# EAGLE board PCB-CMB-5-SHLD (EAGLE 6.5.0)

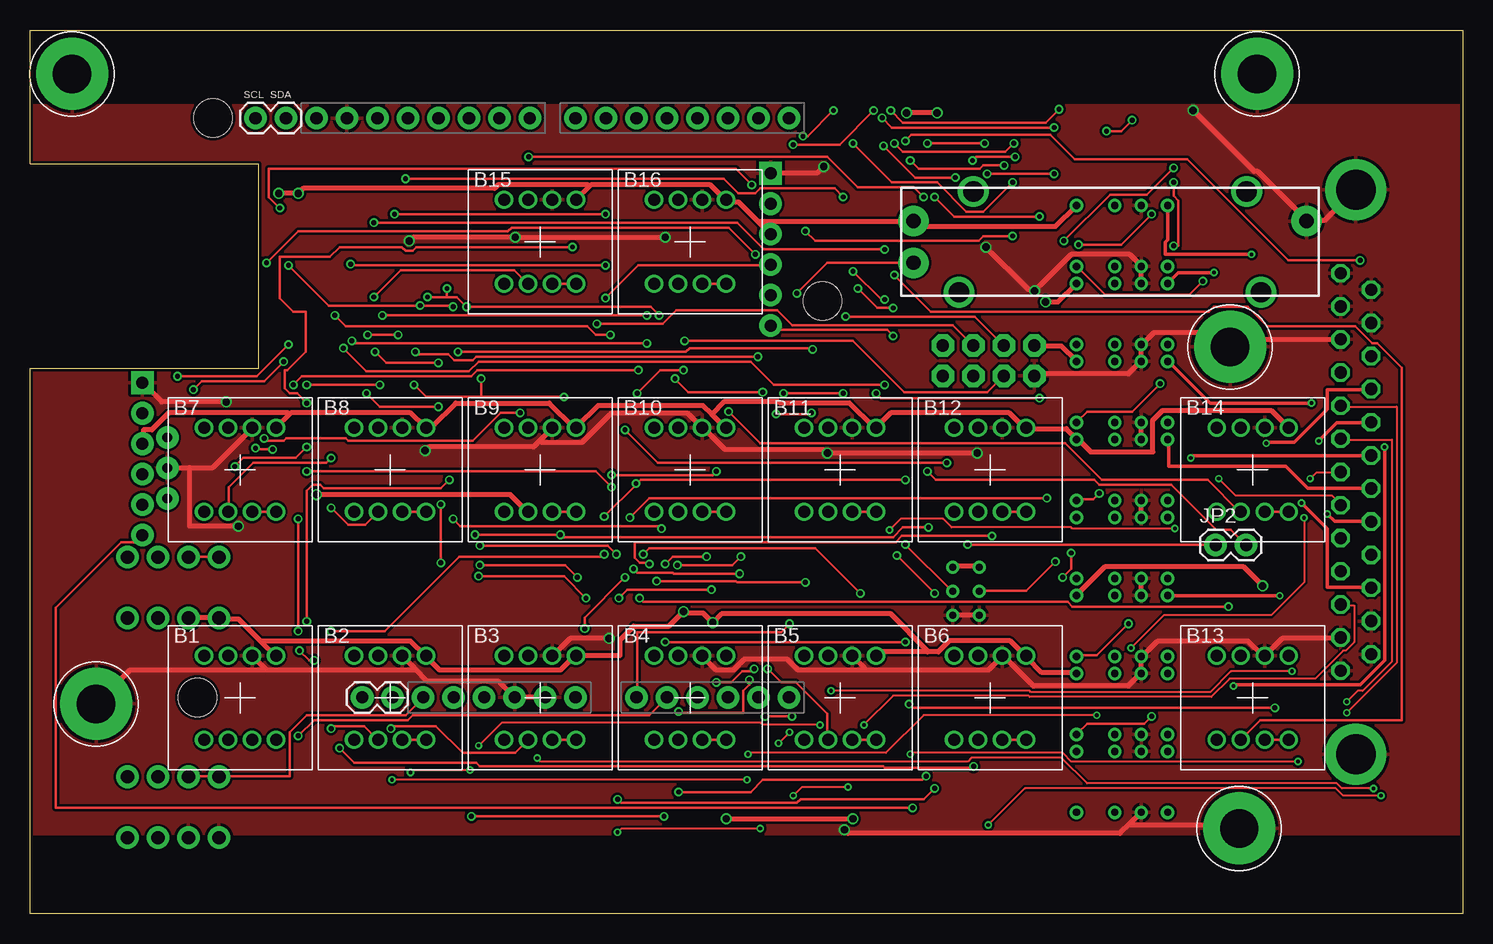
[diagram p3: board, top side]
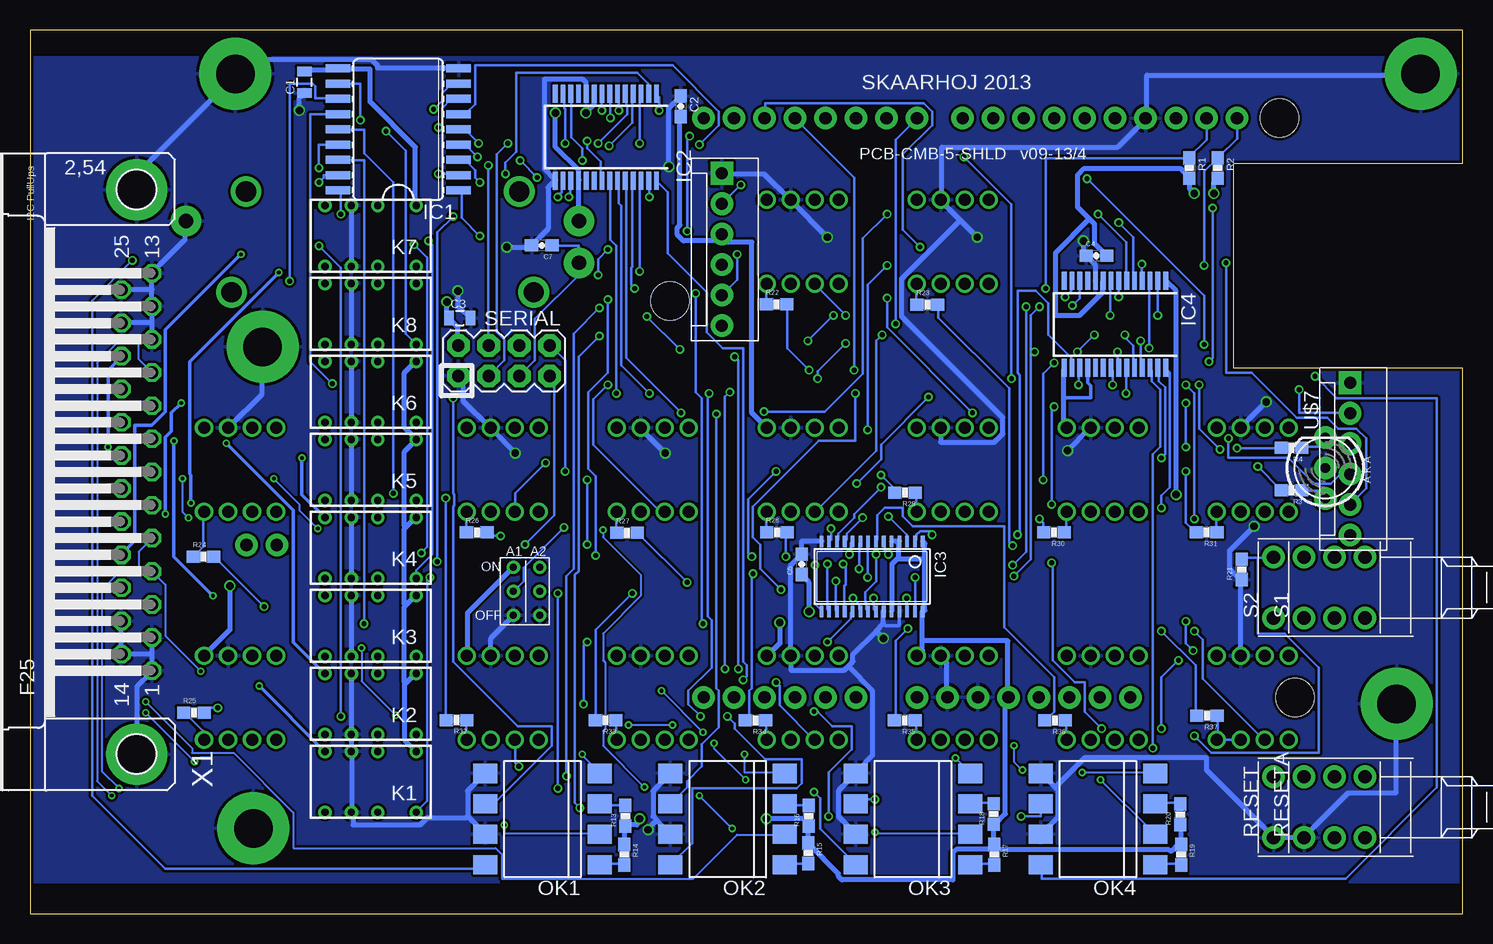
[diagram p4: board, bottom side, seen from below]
Size 119.38 x 73.66 mm. Coordinates in mm from the lower left corner, seen from the top.
Outline: 0,0 0,45.47 19.05,45.47 19.05,62.5 0,62.5 0,73.66 119.38,73.66 119.38,0 0,0
Copper layers (1*16): Top 0.035mm / dielectric 1.5mm / Bottom 0.035mm
Design rules "Fusion_eagle_rule_v1.1": minimum track width 6mil, minimum drill 12mil, track to track 6mil, track to pad 6mil, pad to pad 6mil, via to via 6mil, smd to smd 0mil, copper to edge 10mil, drill to drill 10mil, minimum pad ring 10mil, minimum via ring 6mil, stop-mask expansion 2mil, vias tented up to drill 100mil, thermal gap 10mil
Net classes: 0 default: width 0.203 mm, drill 0.406 mm, clearance 0.203 mm; 1 PWR: width 0.406 mm, drill 0.61 mm, clearance 0.203 mm; 2 RELAY LINES: width 0.305 mm, clearance 0.203 mm; 3 INput lines: clearance 0.203 mm
Holes 3.2 mm at 66.04,51.07 15.24,66.31 13.97,18.05
tRestrict: area 0,0 to 120,6.5; area 0,67.5 to 120,74
bRestrict: area 0,71.5 to 120,74; area 0,0 to 120,2.5

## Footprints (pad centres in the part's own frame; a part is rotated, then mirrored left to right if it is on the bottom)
NKK-NP01 = drill 1: 1 1,3.5; 2 -1,-3.5; L1 3,-3.5; L2 1,-3.5; L3 -1,3.5; L4 -3,3.5; LC1 3,3.5; LC2 -3,-3.5
0805 = smd 0.8 x 1.2: 1 -0.9,0; 2 0.9,0
0603-CAP = smd 1.1 x 1: 1 -0.85,0; 2 0.85,0
DUEMILANOVE_VIAS = drill 1.016 pad 1.88: 3.3V 50.8,13.97; 5V 50.8,16.51; A0 50.8,29.21; A1 50.8,31.75; A2 50.8,34.29; A3 50.8,36.83; A4 50.8,39.37; A5 50.8,41.91; AREF 2.54,2.54; D2 2.54,36.83; D3 2.54,34.29; D4 2.54,31.75; D5 2.54,29.21; D6 2.54,26.67; D7 2.54,24.13; D8 2.54,20.32; D9 2.54,17.78; D10 2.54,15.24; D11 2.54,12.7; D12 2.54,10.16; D13 2.54,7.62; GND@0 50.8,19.05; GND@1 50.8,21.59; GND@2 2.54,5.08; RES 50.8,11.43; RX 2.54,41.91; TX 2.54,39.37; VIN 50.8,24.13
SO18W = smd 0.66 x 2.032: 1 -5.08,-5.029; 2 -3.81,-5.029; 3 -2.54,-5.029; 4 -1.27,-5.029; 5 0,-5.029; 6 1.27,-5.029; 7 2.54,-5.029; 8 3.81,-5.029; 9 5.08,-5.029; 10 5.08,5.029; 11 3.81,5.029; 12 2.54,5.029; 13 1.27,5.029; 14 0,5.029; 15 -1.27,5.029; 16 -2.54,5.029; 17 -3.81,5.029; 18 -5.08,5.029
SSOP28 = smd 0.4 x 1.5: 1 -4.225,-3.625; 2 -3.575,-3.625; 3 -2.925,-3.625; 4 -2.275,-3.625; 5 -1.625,-3.625; 6 -0.975,-3.625; 7 -0.325,-3.625; 8 0.325,-3.625; 9 0.975,-3.625; 10 1.625,-3.625; 11 2.275,-3.625; 12 2.925,-3.625; 13 3.575,-3.625; 14 4.225,-3.625; 15 4.225,3.625; 16 3.575,3.625; 17 2.925,3.625; 18 2.275,3.625; 19 1.625,3.625; 20 0.975,3.625; 21 0.325,3.625; 22 -0.325,3.625; 23 -0.975,3.625; 24 -1.625,3.625; 25 -2.275,3.625; 26 -2.925,3.625; 27 -3.575,3.625; 28 -4.225,3.625
TSSOP28 = smd 0.305 x 0.991: 1 -4.225,-2.918; 2 -3.575,-2.918; 3 -2.925,-2.918; 4 -2.275,-2.918; 5 -1.625,-2.918; 6 -0.975,-2.918; 7 -0.325,-2.918; 8 0.325,-2.918; 9 0.975,-2.918; 10 1.625,-2.918; 11 2.275,-2.918; 12 2.925,-2.918; 13 3.575,-2.918; 14 4.225,-2.918; 15 4.225,2.918; 16 3.575,2.918; 17 2.925,2.918; 18 2.275,2.918; 19 1.625,2.918; 20 0.975,2.918; 21 0.325,2.918; 22 -0.325,2.918; 23 -0.975,2.918; 24 -1.625,2.918; 25 -2.275,2.918; 26 -2.925,2.918; 27 -3.575,2.918; 28 -4.225,2.918
1X02 = drill 1.016 pad 1.88: 1 0,0; 2 2.54,0
MOLEX-1X6 = drill 1.016 pad 1.88 square: 1 0,0 | drill 1.016 pad 1.88: 2 2.54,0; 3 5.08,0; 4 7.62,0; 5 10.16,0; 6 12.7,0
DS2Y = drill 0.6: 1 1.2,0.46; 16 1.2,5.54; O1 4.4,0.46; O2 4.4,5.54; P1 6.6,0.46; P2 6.6,5.54; S1 8.8,0.46; S2 8.8,5.54
DIL8-SMD = smd 1.6 x 2: 1 -3.81,-4.77; 2 -1.27,-4.77; 3 1.27,-4.77; 4 3.81,-4.77; 5 3.81,4.77; 6 1.27,4.77; 7 -1.27,4.77; 8 -3.81,4.77
SLIDER20 = drill 1.194 pad 2.54: 1 -16.383,1.74; 2A -16.383,-1.74; 3 16.383,1.74 | drill 1.702: P$1 -11.392,4.191; P$2 11.392,4.191; P$3 12.598,-4.191; P$4 -12.598,-4.191
0603-RES = smd 1.1 x 1: 1 -0.85,0; 2 0.85,0
PUSHBUTTON = drill 1.1 pad 1.88: 1 2.54,2.54; 2 2.54,-2.54; 3 -2.54,2.54; 4 -2.54,-2.54
2X4 = drill 1.016 pad 1.88 octagon: 1 -3.81,-1.27; 2 -3.81,1.27; 3 -1.27,-1.27; 4 -1.27,1.27; 5 1.27,-1.27; 6 1.27,1.27; 7 3.81,-1.27; 8 3.81,1.27
3.2MMPAD6MM = drill 3.2 pad 6: P$1 0,0
LED5MM-BICOLOR = drill 0.813 pad 1.88: A2 2.54,0; A3 -2.54,0; K1 0,0
2BITADDR = drill 0.6: A1 0,0; A2 2.2,0; H2 0,2; H3 2.2,2; L2 0,-2; L3 2.2,-2
F25HP = drill 1.016 octagon: 1 -16.561,-1.27; 2 -13.792,-1.27; 3 -11.049,-1.27; 4 -8.28,-1.27; 5 -5.512,-1.27; 6 -2.769,-1.27; 7 0,-1.27; 8 2.769,-1.27; 9 5.512,-1.27; 10 8.28,-1.27; 11 11.049,-1.27; 12 13.792,-1.27; 13 16.561,-1.27; 14 -15.189,1.27; 15 -12.421,1.27; 16 -9.652,1.27; 17 -6.909,1.27; 18 -4.14,1.27; 19 -1.372,1.27; 20 1.372,1.27; 21 4.14,1.27; 22 6.909,1.27; 23 9.652,1.27; 24 12.421,1.27; 25 15.189,1.27 | drill 3.302 pad 5.08: G1 -23.52,0; G2 23.52,0

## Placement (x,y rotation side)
B1  NKK-NP01-SINGLECOLOR  [NKK-NP01]  17.5,18 0 top
B2  NKK-NP01-SINGLECOLOR  [NKK-NP01]  30,18 0 top
B3  NKK-NP01-SINGLECOLOR  [NKK-NP01]  42.5,18 0 top
B4  NKK-NP01-SINGLECOLOR  [NKK-NP01]  55,18 0 top
B5  NKK-NP01-SINGLECOLOR  [NKK-NP01]  67.5,18 0 top
B6  NKK-NP01-SINGLECOLOR  [NKK-NP01]  80,18 0 top
B7  NKK-NP01-SINGLECOLOR  [NKK-NP01]  17.5,37 0 top
B8  NKK-NP01-SINGLECOLOR  [NKK-NP01]  30,37 0 top
B9  NKK-NP01-SINGLECOLOR  [NKK-NP01]  42.5,37 0 top
B10  NKK-NP01-SINGLECOLOR  [NKK-NP01]  55,37 0 top
B11  NKK-NP01-SINGLECOLOR  [NKK-NP01]  67.5,37 0 top
B12  NKK-NP01-SINGLECOLOR  [NKK-NP01]  80,37 0 top
B13  NKK-NP01-SINGLECOLOR  [NKK-NP01]  101.88,18 0 top
B14  NKK-NP01-SINGLECOLOR  [NKK-NP01]  101.88,37 0 top
B15  NKK-NP01-SINGLECOLOR  [NKK-NP01]  42.5,56 0 top
B16  NKK-NP01-SINGLECOLOR  [NKK-NP01]  55,56 0 top
C1  100nF  [0805]  96.52,69.31 90 bottom
C2  100nF  [0603-CAP]  65.15,67.31 270 bottom
C3  10uF  [0805]  83.57,49.66 0 bottom
C4  100nF  [0603-CAP]  30.51,54.86 0 bottom
C5  100nF  [0603-CAP]  55.07,29.13 90 bottom
C7  10nF  [0603-CAP]  76.73,55.71 180 bottom
GND  ARDUINO_SHIELDNO_SILK  [DUEMILANOVE_VIAS]  21.34,68.85 270 top
IC1  ULN2803A  [SO18W]  88.7,65.38 90 bottom
IC2  MCP23017SS  [SSOP28]  71.39,64.73 180 bottom
IC3  PCA9685  [TSSOP28]  49.21,28.12 180 bottom
IC4  MCP23017SS  [SSOP28]  28.97,49.12 180 bottom
JP1  [1X02]  27.69,18.05 0 top
JP2  [1X02]  98.81,30.75 0 top
JP3  [MOLEX-1X6]  61.72,61.72 270 bottom
JP4  [1X02]  21.34,66.31 180 top
JP5  [MOLEX-1X6]  9.36,44.26 270 bottom
K1  RELAY5VIM03  [DS2Y]  86,14 180 bottom
K2  RELAY5VIM03  [DS2Y]  86,20.5 180 bottom
K3  RELAY5VIM03  [DS2Y]  86,27 180 bottom
K4  RELAY5VIM03  [DS2Y]  86,33.5 180 bottom
K5  RELAY5VIM03  [DS2Y]  86,40 180 bottom
K6  RELAY5VIM03  [DS2Y]  86,46.5 180 bottom
K7  RELAY5VIM03  [DS2Y]  86,59.5 180 bottom
K8  RELAY5VIM03  [DS2Y]  86,53 180 bottom
OK1  LTV826S  [DIL8-SMD]  76.67,7.9 90 bottom
OK2  LTV826S  [DIL8-SMD]  61.24,7.9 90 bottom
OK3  LTV826S  [DIL8-SMD]  45.81,7.9 90 bottom
OK4  LTV826S  [DIL8-SMD]  30.38,7.9 90 bottom
POT1  10K Linear  [SLIDER20]  90,56 0 top
R1  1K5  [0603-RES]  22.77,62.15 270 bottom
R2  1K5  [0603-RES]  20.4,62.15 270 bottom
R3  270  [0603-RES]  14.24,35.29 180 bottom
R4  270  [0603-RES]  14.24,38.83 180 bottom
R13  330R  [0603-RES]  69.76,8.18 90 bottom
R14  330R  [0603-RES]  69.86,4.93 270 bottom
R15  330R  [0603-RES]  54.53,5.06 270 bottom
R16  330R  [0603-RES]  54.47,8.18 90 bottom
R17  330R  [0603-RES]  39.03,4.93 270 bottom
R18  330R  [0603-RES]  39.06,8.32 90 bottom
R19  330R  [0603-RES]  23.46,4.93 270 bottom
R20  330R  [0603-RES]  23.52,8.3 90 bottom
R21  10K  [0603-RES]  18.41,28.72 90 bottom
R22  100R  [0603-RES]  57.16,50.8 0 bottom
R23  100R  [0603-RES]  44.61,50.77 0 bottom
R24  100R  [0603-RES]  104.91,29.77 0 bottom
R25  100R  [0603-RES]  105.72,16.77 0 bottom
R26  100R  [0603-RES]  82.15,31.79 0 bottom
R27  100R  [0603-RES]  69.62,31.75 0 bottom
R28  100R  [0603-RES]  57.14,31.82 0 bottom
R29  100R  [0603-RES]  46.47,35.11 180 bottom
R30  100R  [0603-RES]  34.04,31.8 180 bottom
R31  100R  [0603-RES]  21.32,31.8 180 bottom
R32  100R  [0603-RES]  83.84,16.16 180 bottom
R33  100R  [0603-RES]  71.41,16.14 180 bottom
R34  100R  [0603-RES]  58.93,16.12 180 bottom
R35  100R  [0603-RES]  46.48,16.12 180 bottom
R36  100R  [0603-RES]  33.96,16.12 180 bottom
R37  100R  [0603-RES]  21.31,16.5 180 bottom
RESET  [PUSHBUTTON]  13.21,8.89 90 bottom
RESETA  [PUSHBUTTON]  10.67,8.89 90 bottom
S1  [PUSHBUTTON]  10.67,27.19 90 bottom
S2  [PUSHBUTTON]  13.21,27.19 90 bottom
SERIAL  M04X2  [2X4]  79.88,46.1 0 bottom
U$4  GNDPAD6MM  [3.2MMPAD6MM]  100,47.25 0 top
U$7  LEDBICOLOR-AKA  [LED5MM-BICOLOR]  11.44,37.16 90 bottom
U$15  GNDPAD6MM  [3.2MMPAD6MM]  100.77,7.12 0 top
U$18  GNDPAD6MM  [3.2MMPAD6MM]  102.26,70 0 top
U$19  2BITADDR  [2BITADDR]  79.1,26.89 0 bottom
U$20  GNDPAD6MM  [3.2MMPAD6MM]  5.5,17.5 0 top
U$21  GNDPAD6MM  [3.2MMPAD6MM]  3.5,70 0 top
X1  DB25F  [F25HP]  110.49,36.83 90 bottom

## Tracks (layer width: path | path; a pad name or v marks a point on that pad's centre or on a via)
5V  (via drill 0.61)
  Top 0.406: v75.59,66.75 v73.05,66.75 | K7.1 87.17,59.03 85.45,57.3 74.07,57.3 73.66,57.71 POT1.1 73.46,57.71 60.86,57.71 60.76,57.61 | v20.73,60.05 v22.35,60.05 22.76,60.45 38.71,60.45 39.01,60.76 46.53,60.76 46.63,60.66 | 46.63,60.66 46.74,60.76 56.69,60.76 57.91,59.54 B16.LC1 58.12,59.33 59.03,59.33 60.76,57.61 | 46.63,60.66 45.52,59.54 B15.LC1 | 60.76,57.61 JP3.3 | 19.3,22.66 17.37,24.59 15.75,24.59 S2.3 15.65,24.69 13.21,24.69 S1.3 | 19.3,22.66 20.42,21.54 B1.LC1 | 19.3,22.66 19.41,22.76 31.7,22.76 32.92,21.54 B2.LC1 33.12,21.34 34.14,20.32 44.2,20.32 45.31,21.44 B3.LC1 45.52,21.54 49.17,21.54 49.17,22.86 50.29,23.98 53.24,23.98 v54.46,25.2 54.56,25.09 56.08,25.09 v56.9,24.28 57.61,24.99 71.73,24.99 74.78,21.95 74.78,21.84 | v58.01,7.92 v68.58,7.92 | 56.79,41.66 57.91,40.54 B10.LC1 | 56.79,41.66 56.08,42.37 47.35,42.37 45.52,40.54 B9.LC1 45.31,40.54 43.28,42.57 35.46,42.57 33.53,40.64 33.12,40.64 B8.LC1 32.92,40.54 31.7,41.76 21.74,41.76 21.64,41.66 | 21.64,41.66 20.52,40.54 B7.LC1 | JP5.3 9.45,39.22 9.45,40.34 10.16,40.34 11.58,41.76 21.54,41.76 21.64,41.66 | K6.1 87.17,46.13 85.95,47.35 83.72,47.35 SERIAL.2 | v84.63,51 85.65,51 87.17,52.53 K8.1 | B14.LC1 104.85,40.54 103.43,41.96 94.39,41.96 93.57,41.15 93.57,38.51 88.39,38.51 87.38,39.52 K5.1 87.17,39.62 86.36,40.44 83.01,40.44 B12.LC1 82.8,40.54 81.58,41.76 71.73,41.76 70.51,40.54 B11.LC1 70.31,40.54 68.28,42.57 62.48,42.57 62.38,42.67 57.81,42.67 56.79,41.66 | U$19.H3 76.91,28.96 79.05,28.96 U$19.H2 | 74.78,21.84 75.69,21.84 76.61,22.76 81.69,22.76 82.91,21.54 B6.LC1 83.11,21.34 84.33,20.12 87.17,20.12 K2.1
  Top 0.406: 74.78,21.84 70.81,21.84 70.51,21.54 B5.LC1 | v102.72,27.33 101.09,28.96 89.61,28.96 87.27,26.62 K3.1
  Bottom 0.305: IC4.18 31.25,44.24 31,44 31,43 33.22,43
  Bottom 0.406: C1.2 96.52,70.31 93.78,70.31 93.78,70.41 IC1.10 93.57,70.41 91.03,70.41 91.03,67.67 87.27,63.91 87.27,59.13 K7.1 | POT1.1 73.66,57.81 73.66,61.06 IC2.18 73.66,61.27 73.66,61.98 75.59,63.91 v75.59,66.75 | v73.05,66.75 72.34,67.46 72.34,68.28 IC2.9 | v20.73,60.05 20.73,60.96 20.42,61.27 R2.2 | v22.35,60.05 22.76,60.45 22.76,61.27 R1.2 22.86,61.47 23.47,62.08 31.6,62.08 32.11,61.57 32.11,58.93 31.09,57.91 | 31.09,57.91 30.68,57.51 30.68,55.88 C4.2 | 31.09,57.91 33.93,55.07 33.93,49.89 31.9,49.89 29.97,51.82 29.97,52.73 IC4.9 | C2.2 65.23,66.45 65.23,57.4 65.43,57.2 65.43,56.59 64.92,56.08 61.77,56.08 61.77,56.59 JP3.3 61.67,55.98 59.23,55.98 59.23,41.76 58.01,40.54 B10.LC1 | IC3.5 47.55,31.09 46.94,31.09 IC3.4 47.04,30.89 47.04,29.67 | 47.04,29.67 47.55,29.16 47.55,25.3 IC3.24 | 45.01,22.76 45.01,21.95 45.41,21.54 B3.LC1 | 45.01,22.76 45.01,25.2 IC3.28 44.81,25.3 44.81,29.57 | 44.81,29.57 44.81,30.89 44.91,30.99 IC3.1 | v54.46,25.2 54.46,27.64 55.07,28.25 C5.1 | v56.9,24.28 56.9,22.55 57.91,21.54 B4.LC1 | 44.81,29.57 46.94,29.57 47.04,29.67 | R20.1 23.47,7.42 23.47,5.79 R19.1 23.67,5.79 24.18,5.28 24.38,5.28 24.49,5.38 39.01,5.38 R17.1 | R14.1 69.8,5.79 69.8,7.32 R13.1 69.6,7.42 68.78,7.42 68.78,7.72 v68.58,7.92 | R17.1 39.12,5.79 39.12,7.42 R18.1 38.91,7.52 38.1,8.33 38.1,17.78 37.9,17.98 GND.5V 37.9,18.19 37.9,22.76 45.01,22.76 | R17.1 39.12,5.59 39.12,5.38 42.16,5.38 42.47,5.08 42.47,2.85 51.71,2.85 52.02,3.15 52.02,3.35 54.46,5.79 R15.1 54.56,5.99 54.56,7.32 R16.1 54.56,7.52 54.56,7.92 v58.01,7.92 | IC4.15 33.22,45.41 33.22,43 33.22,40.74 33.02,40.54 B8.LC1
  Bottom 0.406: SERIAL.2 83.72,47.45 83.72,48.87 84.43,49.58 C3.1 84.63,49.78 v84.63,51 | K6.1 87.27,46.02 88.19,45.11 88.19,40.54 87.27,39.62 K5.1 87.27,39.42 88.19,38.51 88.19,32.31 88.09,32.21 | U$19.H2 79.15,28.85 82.91,25.09 82.91,21.54 B6.LC1 | K1.1 88.19,14.53 88.19,19.1 88.09,19.2 | 88.09,19.2 87.27,20.02 K2.1 | 88.09,25.7 88.19,25.6 88.19,19.3 88.09,19.2 | 88.09,25.7 87.27,26.52 K3.1 | 88.09,32.21 88.19,32.11 88.19,25.81 88.09,25.7 | 88.09,32.21 87.27,33.02 K4.1 | v102.72,27.33 102.72,23.67 104.85,21.54 B13.LC1
A1  (via drill 0.41)
  Top 0.203: v74.88,32.21 72.75,32.21 71.93,31.39 44.4,31.39 v44.2,31.6 v37.08,31.6 | v75.39,59.74 77.01,58.12 v84.12,58.12 | v85.45,29.36 83.01,26.92 79.15,26.92 U$19.A1
  Bottom 0.203: v44.2,31.6 44.2,31.9 45.21,31.9 45.52,31.6 45.52,31.19 45.62,31.09 IC3.2 | v74.88,32.21 78.23,28.85 78.23,27.74 79.05,26.92 U$19.A1 | v37.08,31.6 36.88,31.8 36.88,44.91 37.08,45.11 37.08,51.92 35.56,51.92 34.54,50.9 34.54,48.26 32.61,46.33 32.61,45.52 IC4.16 | v75.39,59.74 75.39,59.84 75.08,60.15 75.08,60.96 74.98,61.06 IC2.16 | v84.12,58.12 85.45,56.79 v85.45,29.36
A1CFG  (via drill 0.41)
  Top 0.203: v22.35,14.83 23.67,16.15 31.5,16.15 31.9,16.56 51.61,16.56 53.03,17.98 GND.A1 | S1.1 13.21,29.77 15.75,29.77 S2.1
  Bottom 0.203: 17.07,29.67 15.75,29.67 S2.1 | 17.07,29.67 18.39,29.67 R21.2 | v22.35,14.83 20.93,13.41 11.99,13.41 11.99,20.52 14.83,23.37 17.07,23.37 17.07,29.67
A2  (via drill 0.41)
  Top 0.203: 50.55,35.81 50.9,36.17 v72.95,36.17 | 50.55,35.81 v47.85,33.12 | v72.95,30.79 76.81,26.92 U$19.A2 | v32,44.09 33.02,43.08 37.59,43.08 | v44.5,43.08 37.59,43.08 | v50.49,35.87 50.55,35.81 | v74.47,59.74 73.66,60.55 68.99,60.55 66.45,63.09 v41.55,63.09 | 37.59,43.08 v37.59,44.6
  Bottom 0.203: v47.85,33.12 46.33,31.6 46.33,31.09 IC3.3 | v72.95,30.79 v72.95,36.17 | v32,44.09 32,45.31 31.9,45.41 IC4.17 | v44.5,43.08 48.46,39.12 48.46,37.9 v50.49,35.87 | v74.47,59.74 74.37,59.84 74.37,61.06 IC2.17 | v41.55,63.09 37.59,59.13 v37.59,44.6
D2  (via drill 0.41)
  Top 0.203: v17.07,37.29 17.78,38 22.15,38 v23.06,38.91 | v23.06,42.57 22.25,43.38 21.64,43.38 21.23,43.79 21.23,45.31 21.44,45.31 22.96,46.84 22.96,50.19 21.95,50.19 20.83,51.31 20.83,54.76 24.99,54.76 25.81,55.58 30.99,55.58 31.29,55.27 31.9,55.27 32.21,55.58 v45.21,55.58
  Bottom 0.203: v17.07,37.29 15.14,35.36 R3.2 | v23.06,42.57 v23.06,38.91 | v45.21,55.58 46.63,57 46.63,63.3 44.2,65.73 44.2,66.85 44.91,67.56 58.12,67.56 58.12,66.34 GND.D2
D3  (via drill 0.41)
  Top 0.203: v18.8,38.81 18.9,38.71 v20.22,38.71 | v21.95,44.09 22.66,44.81 36.78,44.81 37.29,45.31 v50.7,45.31
  Bottom 0.203: v18.8,38.81 15.14,38.81 R4.2 | v20.22,38.71 21.95,40.44 v21.95,44.09 | v50.7,45.31 50.7,61.37 55.58,66.24 GND.D3
DISP_DATA_OUT  (via drill 0.41)
  Top 0.203: v47.24,49.17 52.73,49.17 53.85,50.29 62.28,50.29 63.5,49.07 76.91,49.07 78.54,47.45 SERIAL.6
  Bottom 0.203: v47.24,49.17 47.24,64.52 45.52,66.24 GND.D7
GND  (via drill 0.61)
  Top 0.406: v66.14,62.28 65.63,61.77 61.77,61.77 JP3.1 | v31.6,56.08 31.9,56.39 v40.44,56.39 v52.93,56.39 | 13.31,37.19 11.48,37.19 U$7.K1 | 13.31,37.19 15.24,37.19 18.49,40.44 B7.1 | v16.36,42.67 10.97,42.67 9.45,44.2 JP5.1 | 32.11,20.42 33.12,19.41 39.01,19.41 40.34,18.09 GND.GND@0 40.54,18.09 42.88,18.09 GND.GND@1 | 32.11,20.42 31.09,21.44 B2.1 | 19.61,20.42 19.71,20.32 32,20.32 32.11,20.42 | 19.61,20.42 18.59,21.44 B1.1 | 13.31,37.19 13.31,32.31 v17.37,32.31 | U$20.P$1 5.59,17.58 8.33,20.32 19.51,20.32 19.61,20.42 | v96.93,66.95 102.01,61.87 102.31,61.87 106.38,57.81 POT1.3 106.58,57.81 107.9,57.81 110.44,60.35 X1.G2 | X1.11 109.22,47.85 100.58,47.85 100.08,47.35 U$4.P$1 99.87,47.35 98.75,48.46 93.67,48.46 92.76,47.55 K8.P2 92.56,47.45 92.56,46.13 K6.P1 92.46,45.92 91.54,45.01 83.82,45.01 83.72,44.91 SERIAL.1 | v32.92,38.61 33.22,38.91 41.96,38.91 42.47,39.42 | 42.47,39.42 43.48,40.44 B9.1 | 42.47,39.42 42.57,39.32 46.02,39.32 48.46,41.76 54.76,41.76 55.98,40.54 B10.1 56.19,40.44 57.91,38.71 66.14,38.71 v66.45,38.41 v78.94,38.41 | K8.P1 92.56,52.63 92.56,53.85 K7.P2 92.56,54.05 91.64,54.97 86.77,54.97 v83.72,51.92 83.62,52.02 83.21,52.02 v79.65,55.58 | X1.2 109.22,22.96 104.34,22.96 102.92,21.54 B13.1 102.72,21.54 101.5,22.76 93.98,22.76 92.76,21.54 K3.P2 92.56,21.44 92.56,20.12 K2.P1 92.46,19.91 91.54,19 83.62,19 81.18,21.44 B6.1 80.97,21.44 79.86,20.32 69.7,20.32 69.6,20.42 | U$19.L3 76.91,24.89 79.05,24.89 U$19.L2 | 69.6,20.42 68.58,21.44 B5.1 | K5.P1 92.56,39.62 92.56,40.95 K6.P2 | K4.P1 92.56,33.12 92.56,34.44 K5.P2 | K3.P1 92.56,26.62 92.56,27.94 K4.P2
  Top 0.406: v67.87,7.01 68.17,6.71 90.83,6.71 91.64,7.52 | 91.64,7.52 92.56,8.43 K1.P2 | U$15.P$1 100.69,7.21 100.48,7.42 91.75,7.42 91.64,7.52 | B4.1 56.08,21.44 57.2,20.32 58.62,20.32 59.54,21.23 63.09,21.23 64.01,20.32 69.49,20.32 69.6,20.42 | v48.26,22.96 45.01,22.96 43.59,21.54 B3.1
  Bottom 0.305: IC3.25 46.94,24.07 47,24 48.08,24 48.26,24.18
  Bottom 0.406: v66.14,62.28 66.14,67.16 65.23,68.07 C2.1 | JP3.1 61.67,61.67 58.22,61.67 56.08,59.54 B16.1 55.88,59.33 v52.93,56.39 | IC4.10 30.58,52.83 30.58,54.05 31.29,54.76 C4.1 31.39,55.07 31.6,55.27 v31.6,56.08 | 41.86,57.81 43.48,59.44 B15.1 43.38,59.64 43.38,63.91 28.75,63.91 26.42,66.24 GND.GND@2 26.31,66.45 26.31,69.9 3.56,69.9 U$21.P$1 | 41.86,57.81 v40.44,56.39 | 33.93,10.57 35.05,11.68 OK4.5 | 33.93,10.57 33.73,10.36 33.73,8.03 35.05,6.71 OK4.7 | 33.93,10.57 31.5,13.01 21.34,13.01 21.34,11.99 15.75,6.4 RESET.3 15.65,6.4 13.21,6.4 RESETA.3 13.11,6.5 9.55,10.06 5.59,10.06 5.59,17.48 U$20.P$1 | v16.36,42.67 18.49,40.54 B7.1 | B3.1 43.48,21.44 42.98,20.93 42.98,18.09 GND.GND@1 | B1.1 18.49,21.54 18.49,27.84 R21.1 18.59,27.94 19.41,28.75 19.41,30.28 v17.37,32.31 | IC1.9 83.72,70.51 90.42,70.51 90.42,70.71 90.93,71.22 102.21,71.22 102.21,70 U$18.P$1 102.31,69.8 110.44,61.67 110.44,60.35 X1.G2 | B14.1 102.82,40.54 100.08,43.28 100.08,47.24 U$4.P$1 | 109.22,49.28 X1.12 109.22,52.02 | 109.22,49.28 X1.11 | 109.22,52.02 X1.13 109.12,53.54 106.48,56.19 106.48,57.71 POT1.3 | 109.22,49.28 111.76,49.28 X1.24 | 109.22,52.02 X1.25 | v96.93,66.95 96.93,67.97 96.52,68.38 C1.1 | v32.92,38.61 31.09,40.44 B8.1 | v66.45,38.41 68.48,40.44 B11.1 | IC2.10 73.05,68.38 73.05,69.29 73.36,69.6 76.5,69.6 76.5,62.08 75.69,61.27 IC2.15 75.69,61.06 76.2,60.55 76.2,57.1 77.52,55.78 C7.2 77.72,55.58 v79.65,55.58 | v83.72,51.92 83.72,50.7 82.7,49.68 C3.2 | K7.P1 92.56,59.03 92.56,54.05 K7.P2 | X1.2 109.22,21.64 | 109.22,21.64 X1.1 109.32,20.12 110.44,19 110.44,13.31 X1.G1 | 109.22,21.64 X1.14 X1.15
  Bottom 0.406: OK3.7 50.6,6.71 52.02,8.13 52.02,10.26 50.6,11.68 OK3.5 50.49,11.89 49.17,13.21 49.17,18.59 51.21,20.62 | IC3.14 53.44,31.09 55.07,31.09 55.07,30.07 C5.2 55.17,29.87 55.98,29.06 55.98,21.64 B4.1 55.98,21.44 55.98,20.32 51.51,20.32 51.21,20.62 | 48.87,23.57 50.8,21.64 50.8,21.03 51.21,20.62 | 48.87,23.57 48.26,24.18 48.26,25.2 IC3.23 | U$19.L2 79.15,24.79 80.97,22.96 80.97,21.54 B6.1 | SERIAL.1 83.62,44.81 83.31,44.5 83.31,42.77 81.08,40.54 B12.1 80.87,40.34 v78.94,38.41 | 82.91,8.13 81.48,6.71 OK1.7 | 82.91,8.13 82.91,10.26 81.48,11.68 OK1.5 | 67.16,7.82 67.46,8.13 67.46,10.26 66.04,11.68 OK2.5 | 67.16,7.82 66.04,6.71 OK2.7 | K2.P1 92.56,20.02 92.56,15.14 K2.P2 92.56,14.94 92.56,13.72 K1.P1 92.56,13.51 92.56,8.53 K1.P2 92.46,8.33 92.46,7.42 86.87,7.42 86.26,8.03 83.01,8.03 82.91,8.13 | K3.P1 92.56,26.52 92.56,21.54 K3.P2 | K4.P1 92.56,33.02 92.56,28.04 K4.P2 | K5.P1 92.56,39.52 92.56,34.54 K5.P2 | K6.P1 92.56,46.02 92.56,41.05 K6.P2 | 67.16,7.82 67.87,7.11 v67.87,7.01 | K8.P1 92.56,52.53 92.56,47.55 K8.P2 | 48.87,23.57 v48.26,22.96 | 41.86,57.81 46.74,52.93 46.74,49.78 38.3,41.35 38.3,40.03 39.01,39.32 43.48,39.32 43.48,40.44 B9.1
  pour Top: 0,0 120,0 120,74 0,74
  pour Bottom: 0,0 120,0 120,74 0,74
GPA0  (via drill 0.41)
  Top 0.203: v23.06,44.09 v29.16,44.09 | v22.35,23.57 v22.35,32.92
  Bottom 0.203: v29.16,44.09 29.16,45.31 29.26,45.41 IC4.21 | v23.06,44.09 22.35,43.38 v22.35,32.92 | v22.35,23.57 21.64,22.86 21.64,19.61 16.56,14.53 B1.2
GPA1  (via drill 0.41)
  Top 0.203: v28.75,46.84 29.67,45.92 v34.04,45.92 | v34.95,36.17 34.24,35.46 24.49,35.46 24.18,35.76 23.57,35.76 23.06,35.26 v23.06,24.38 | v22.45,21.95 23.27,21.13 v23.67,21.13 | v25.09,15.44 25.3,15.65 27.84,15.65 28.96,14.53 B2.2
  Bottom 0.203: v28.75,46.84 28.75,45.62 28.65,45.52 IC4.22 | v34.04,45.92 34.95,45.01 v34.95,36.17 | v23.06,24.38 23.06,22.55 v22.45,21.95 | v23.67,21.13 25.09,19.71 v25.09,15.44
GPA2  (via drill 0.41)
  Top 0.203: v28.04,43.38 29.16,42.27 v34.04,42.27 | v34.24,29.26 v34.24,34.14 | v30.07,15.44 30.28,15.65 33.83,15.65 36.07,13.41 40.44,13.41 41.45,14.43 B3.2
  Bottom 0.203: v28.04,43.38 28.04,45.41 IC4.23 | v34.04,42.27 34.24,42.06 v34.24,34.14 | v34.24,29.26 34.14,29.16 34.14,21.13 32.31,19.3 31.5,19.3 31.5,16.87 v30.07,15.44
GPA3  (via drill 0.41)
  Top 0.203: v30.68,48.26 v28.14,48.26 | v32.11,46.84 32.31,46.63 34.85,46.63 35.36,46.13 36.88,46.13 37.19,46.43 v60.66,46.43 | v60.35,20.42 60.15,20.22 59.33,20.22 58.42,19.3 v57.2,19.3
  Bottom 0.203: v28.14,48.26 28.14,48.06 27.43,47.35 27.43,45.52 IC4.24 | v32.11,46.84 v30.68,48.26 | v60.66,46.43 60.35,46.13 v60.35,20.42 | v57.2,19.3 56.9,19 56.9,17.37 54.05,14.53 B4.2
GPA4  (via drill 0.41)
  Top 0.203: v26.82,47.75 27.03,47.55 v51.41,47.55 | v53.75,44.6 54.86,43.48 v61.06,43.48 | v61.47,20.42 62.59,19.3 63.8,19.3 66.45,16.66 66.45,14.53 B5.2
  Bottom 0.203: v26.82,47.75 26.82,45.62 26.72,45.52 IC4.25 | v51.41,47.55 53.75,45.21 v53.75,44.6 | v61.06,43.48 61.47,43.08 v61.47,20.42
GPA5  (via drill 0.41)
  Top 0.203: v25.81,13.82 27.03,12.6 37.19,12.6 37.49,12.29 71.12,12.29 71.22,12.19 78.54,12.19 v78.64,12.29
  Bottom 0.203: v25.81,13.82 25.81,38.3 25.2,38.91 25.2,43.69 25.91,44.4 25.91,45.31 26.01,45.41 IC4.26 | v78.64,12.29 78.94,12.6 78.94,14.43 B6.2
GPA6  (via drill 0.41)
  Top 0.203: v25.09,38 24.69,37.59 18.59,37.59 16.56,35.56 16.56,33.53 B7.2
  Bottom 0.203: v25.09,38 24.79,38.3 24.79,43.89 25.3,44.4 25.3,45.41 IC4.27
GPA7  (via drill 0.41)
  Top 0.203: v25.09,33.83 26.52,32.41 27.94,32.41 28.96,33.43 B8.2
  Bottom 0.203: v25.09,33.83 25.09,34.85 24.38,35.56 24.38,45.11 24.69,45.41 IC4.28
GPB0  (via drill 0.61)
  Top 0.406: v23.88,34.95 40.03,34.95 41.45,33.53 B9.2
  Bottom 0.406: v23.88,34.95 23.88,51.92 24.69,52.73 IC4.1
GPB1  (via drill 0.41)
  Top 0.203: v25.4,49.89 26.31,48.97 46.43,48.97 47.14,48.26 v48.36,48.26
  Bottom 0.203: v25.4,49.89 IC4.2 | v48.36,48.26 48.87,47.75 48.87,38.61 53.95,33.53 B10.2
GPB2  (via drill 0.41)
  Top 0.203: v26.11,47.14 28.04,45.21 36.58,45.21 37.39,46.02 60.05,46.02 61.98,44.09 v71.22,44.09
  Bottom 0.203: v26.11,47.14 26.11,52.73 IC4.3 | v71.22,44.09 72.44,42.88 72.44,39.12 66.85,33.53 66.55,33.53 B11.2
GPB3  (via drill 0.41)
  Top 0.203: v26.72,54.15 26.82,54.05 v47.95,54.05 | v49.58,40.34 52.32,37.59 v76.4,37.59
  Bottom 0.203: v26.72,54.15 26.72,52.83 IC4.4 | v47.95,54.05 49.58,52.43 v49.58,40.34 | v76.4,37.59 78.94,35.05 78.94,33.53 B12.2
GPB4  (via drill 0.41)
  Top 0.203: v28.65,57.61 58.93,57.61 61.16,55.37 v71.22,55.37 | v72.03,53.24 75.08,50.19 98.25,50.19 98.65,50.6 101.5,50.6 103.12,48.97 110.44,48.97 111.86,47.55 112.27,47.55 114.3,45.52 114.3,16.15 102.51,16.15 100.89,14.53 B13.2
  Bottom 0.203: v28.65,57.61 27.43,56.39 27.43,52.83 IC4.5 | v71.22,55.37 72.03,54.56 v72.03,53.24
GPB5  (via drill 0.41)
  Top 0.203: v47.95,58.32 v30.38,58.32 | v58.22,41.86 60.86,39.22 86.26,39.22 89.31,36.17 98.15,36.17 100.79,33.53 B14.2
  Bottom 0.203: v30.38,58.32 28.04,55.98 28.04,52.83 IC4.6 | v47.95,58.32 49.99,56.29 49.99,45.01 53.14,41.86 v58.22,41.86
GPB6  (via drill 0.41)
  Top 0.203: v28.65,51.41 30.89,53.65 40.34,53.65 41.45,52.53 B15.2
  Bottom 0.203: v28.65,51.41 IC4.7
GPB7  (via drill 0.41)
  Top 0.203: v51.41,49.89 v29.36,49.89
  Bottom 0.203: v29.36,49.89 29.36,52.73 IC4.8 | v51.41,49.89 53.95,52.43 B16.2
I2C_SCL  (via drill 0.41)
  Top 0.203: v73.36,62.79 74.07,62.08 79.15,62.08 79.45,62.38 v81.18,62.38 | v46.33,26.31 44.5,28.14 v37.39,28.14 | v35.26,50.6 35.15,50.7 v32.51,50.7 24.89,50.7 v21.54,54.05 | v67.97,49.78 78.74,49.78 81.08,47.45 SERIAL.4 | v65.23,47.04 65.13,47.14 54.97,47.14 54.66,46.84 v35.66,46.84
  Bottom 0.203: v73.36,62.79 73.36,63.8 74.27,64.72 74.27,68.28 IC2.12 | v81.18,62.38 81.18,47.45 SERIAL.4 | JP4.2 18.8,64.62 20.32,63.09 R2.1 20.42,62.99 21.54,61.87 v21.54,54.05 | v46.33,26.31 46.33,25.3 IC3.26 | v37.39,28.14 35.97,29.57 35.97,46.84 | 35.97,46.84 35.97,49.89 v35.26,50.6 | v32.51,50.7 31.9,51.31 31.9,52.73 IC4.12 | v65.23,47.04 v67.97,49.78 | 35.97,46.84 v35.66,46.84
I2C_SDA  (via drill 0.41)
  Top 0.203: v79.55,64.21 v74.78,64.21 | v45.62,28.04 44.6,29.06 v37.49,29.06 | v33.12,51.41 34.75,51.41 | 34.75,51.41 35.56,51.41 v36.37,50.6 51.71,50.6 v52.43,49.89 | 34.75,51.41 v34.75,52.12 | v54.56,47.75 68.58,47.75 72.85,43.48 79.76,43.48 81.08,44.81 SERIAL.3
  Bottom 0.203: v74.78,64.21 74.78,67.06 74.88,67.16 74.88,68.28 IC2.13 | v79.55,64.21 80.47,63.3 80.47,48.46 79.86,47.85 79.86,46.13 81.08,44.91 SERIAL.3 | JP4.1 21.34,64.52 22.76,63.09 R1.1 22.86,62.99 34.75,62.99 v34.75,52.12 | v45.62,28.04 45.62,25.3 IC3.27 | v37.49,29.06 36.37,30.18 v36.37,50.6 | v33.12,51.41 32.61,51.92 32.61,52.73 IC4.13 | v52.43,49.89 v54.56,47.75
L0
  Bottom 0.203: R37.1 20.42,16.46 20.42,14.53 B1.L1 20.32,14.53 18.59,14.53 B1.L2
L1
  Top 0.203: B2.L2 31.09,14.53 32.92,14.53 B2.L1
  Bottom 0.203: R36.1 33.02,16.05 33.02,14.53 B2.L1
L2
  Top 0.203: B3.L2 43.59,14.53 45.41,14.53 B3.L1
  Bottom 0.203: R35.1 45.62,16.05 45.52,15.95 45.52,14.53 B3.L1
L3
  Top 0.203: B4.L2 56.08,14.53 57.91,14.53 B4.L1
  Bottom 0.203: R34.1 58.01,16.05 58.01,14.53 B4.L1
L4
  Top 0.203: B5.L2 68.58,14.53 70.41,14.53 B5.L1
  Bottom 0.203: R33.1 70.51,16.05 70.51,14.53 B5.L1
L5
  Top 0.203: B6.L2 81.08,14.53 82.91,14.53 B6.L1
  Bottom 0.203: R32.1 83.01,16.15 83.01,14.53 B6.L1
L6
  Top 0.203: B7.L2 18.59,33.53 20.42,33.53 B7.L1
  Bottom 0.203: R31.1 20.52,31.8 20.52,33.43 B7.L1
L7
  Top 0.203: B8.L2 31.09,33.53 32.92,33.53 B8.L1
  Bottom 0.203: R30.1 33.12,31.8 33.02,31.9 33.02,33.43 B8.L1
L8
  Top 0.203: B9.L2 43.59,33.53 45.41,33.53 B9.L1
  Bottom 0.203: R29.1 45.62,35.05 45.52,34.95 45.52,33.53 B9.L1
L9
  Top 0.203: B10.L2 56.08,33.53 57.91,33.53 B10.L1
  Bottom 0.203: R28.1 58.01,31.9 58.01,33.43 B10.L1
L10
  Top 0.203: B11.L2 68.58,33.53 70.41,33.53 B11.L1
  Bottom 0.203: R27.1 70.51,31.8 70.51,33.43 B11.L1
L11
  Top 0.203: B12.L2 81.08,33.53 82.91,33.53 B12.L1
  Bottom 0.203: R26.1 83.01,33.43 B12.L1
L12
  Top 0.203: B13.L2 102.92,14.53 104.85,14.53 B13.L1
  Bottom 0.203: R25.1 106.48,16.76 104.95,15.24 104.95,14.53 B13.L1
L13
  Top 0.203: B14.L2 102.92,33.53 104.85,33.53 B14.L1
  Bottom 0.203: R24.1 105.66,29.87 104.95,30.58 104.95,33.43 B14.L1
L14
  Top 0.203: B15.L2 43.59,52.53 45.41,52.53 B15.L1
  Bottom 0.203: R23.1 45.52,50.8 45.52,52.43 B15.L1
L15
  Top 0.203: B16.L2 56.08,52.53 57.91,52.53 B16.L1
  Bottom 0.203: R22.1 58.01,50.9 58.01,52.43 B16.L1
N$1  (via drill 0.3)
  Top 0.305: v100.28,19 100.38,19.1 110.85,19.1 112.88,21.13 v112.88,38.91
  Bottom 0.305: v100.28,19 94.89,13.61 K1.S1 | v112.88,38.91 112.88,45.31 111.76,46.43 X1.23
N$2  (via drill 0.41)
  Top 0.203: v52.63,32.11 52.43,32.31 35.87,32.31 v35.26,32.92
  Bottom 0.203: v52.63,32.11 52.63,31.19 52.73,31.09 IC3.13 | v35.26,32.92 34.95,32.61 34.95,31.8 R30.2
N$3  (via drill 0.41)
  Top 0.203: v19.51,39.62 19.71,39.42 21.13,39.42 21.34,39.62 26.31,39.62 26.52,39.42 36.88,39.42 39.22,41.76 v40.84,41.76 | v47.95,51.31 50.7,54.05 61.67,54.05 JP3.4
  Bottom 0.203: v19.51,39.62 19.51,38 14.53,38 12.5,35.97 12.5,35.87 10.97,35.87 10.26,36.58 9.45,36.58 JP5.4 | v40.84,41.76 47.95,48.87 v47.95,51.31
N$4  (via drill 0.41)
  Top 0.203: v93.47,58.32 90.93,55.78 v87.38,55.78 | v86.77,30.07 86.77,28.75 v86.06,28.04
  Bottom 0.203: v93.47,58.32 93.47,60.05 93.67,60.25 IC1.18 | v87.38,55.78 86.26,54.66 86.26,30.58 v86.77,30.07 | v86.06,28.04 86.26,27.84 86.26,9.45 87.17,8.53 K1.16
N$5  (via drill 0.41)
  Top 0.203: v66.95,66.95 64.82,64.82 v64.41,64.82 | v64.62,56.9 65.43,56.08 79.05,56.08 79.45,56.49 v81.89,56.49
  Bottom 0.203: v66.95,66.95 66.95,68.07 67.16,68.28 IC2.1 | v64.41,64.82 64.62,64.62 v64.62,56.9 | v81.89,56.49 83.41,58.01 83.41,60.05 83.62,60.25 IC1.1
N$6  (via drill 0.3)
  Top 0.305: v103.02,39.22 103.12,39.32 105.36,39.32 108.1,42.06 108.1,43.69 111.76,43.69 X1.22
  Bottom 0.305: v103.02,39.22 97.43,33.63 97.43,22.66 94.89,20.12 K2.S1
N$7
  Bottom 0.203: R4.1 13.31,38.91 11.48,38.91 11.48,39.62 U$7.A2
N$8  (via drill 0.41)
  Top 0.203: v19.71,54.25 22.35,56.9 39.83,56.9 40.13,57.2 58.22,57.2 v60.45,54.97
  Bottom 0.203: v19.71,54.25 19.71,45.11 17.58,45.11 13.82,41.35 11.28,41.35 10.36,40.44 8.84,40.44 8.03,39.62 8.03,35.46 9.35,34.14 JP5.5 | v60.45,54.97 60.45,52.83 JP3.5
N$9  (via drill 0.41)
  Top 0.203: v95.3,60.96 95.3,59.84 95.71,59.44 95.71,55.68 v95.3,55.68 | v93.47,16.46 92.86,15.85 88.09,15.85 87.27,15.04 K2.16
  Bottom 0.203: v95.3,60.96 94.89,61.37 94.89,61.57 93.78,61.57 IC1.17 | v95.3,55.68 93.47,53.85 v93.47,16.46
N$10  (via drill 0.3)
  Top 0.305: v104.14,26.52 94.89,26.52 K3.S1 | v107.39,39.42 108.92,40.95 111.76,40.95 X1.21
  Bottom 0.305: v104.14,26.52 107.39,29.77 v107.39,39.42
N$11
  Bottom 0.203: R3.1 13.31,35.26 11.48,35.26 11.48,34.65 U$7.A3
N$12  (via drill 0.41)
  Top 0.203: v13.61,43.69 14.33,44.4 19.51,44.4 v21.13,46.02 | v20.83,58.83 19.91,59.74 19.91,62.08 58.83,62.08 v60.15,60.76
  Bottom 0.203: v13.61,43.69 13.61,41.76 9.45,41.76 JP5.2 | v21.13,46.02 20.83,46.33 v20.83,58.83 | JP3.2 v60.15,60.76
N$13  (via drill 0.41)
  Top 0.203: v91.54,24.18 88.9,21.54 87.27,21.54 K3.16
  Bottom 0.203: v91.54,24.18 91.54,62.79 93.67,62.79 IC1.16
N$14  (via drill 0.3)
  Top 0.305: v96.72,38 96.93,38.2 X1.20
  Bottom 0.305: v96.72,38 96.72,34.95 94.89,33.12 K4.S1
N$17  (via drill 0.41)
  Top 0.203: v95.3,62.18 93.07,59.94 90.02,59.94 v86.16,56.08
  Bottom 0.203: v95.3,62.18 95.3,64.11 93.78,64.11 IC1.15 | v86.16,56.08 85.85,55.78 85.85,29.97 87.17,28.65 87.17,28.04 K4.16
N$18
  Top 0.305: X1.19 106.48,35.46 104.65,37.29 94.89,37.29 94.89,39.52 K5.S1
N$19  (via drill 0.41)
  Top 0.203: v48.46,35.56 47.14,36.88 v23.06,36.88
  Bottom 0.203: v48.46,35.56 50.7,33.33 50.7,33.02 52.02,31.7 52.02,31.19 52.12,31.09 IC3.12 | v23.06,36.88 23.06,32.61 22.25,31.8 R31.2
N$21  (via drill 0.41)
  Top 0.203: v89.1,35.05 88.59,34.54 87.27,34.54 K5.16
  Bottom 0.203: v89.1,35.05 89.1,60.96 91.54,63.4 91.54,65.33 93.67,65.33 IC1.14
N$22  (via drill 0.3)
  Top 0.305: v106.78,42.57 98.35,42.57 94.89,46.02 K6.S1 | v108.1,33.33 108.71,32.72 111.76,32.72 X1.18
  Bottom 0.305: v106.78,42.57 107.59,41.76 107.59,40.23 108.1,39.73 v108.1,33.33
N$23  (via drill 0.41)
  Top 0.203: v49.99,33.02 51.61,34.65 v84.73,34.65
  Bottom 0.203: v49.99,33.02 51.31,31.7 51.31,31.19 51.41,31.09 IC3.11 | v84.73,34.65 84.73,16.26 R32.2
N$25  (via drill 0.41)
  Top 0.203: v94.18,44.2 91.85,41.86 88.09,41.86 87.27,41.05 K6.16
  Bottom 0.203: v94.18,44.2 96.01,46.02 96.01,66.65 93.78,66.65 IC1.13
N$26  (via drill 0.3)
  Top 0.305: v101.8,54.97 94.59,54.97 94.59,55.98 94.79,56.19 K7.S1
  Bottom 0.305: v101.8,54.97 108.1,48.67 108.1,41.86 109.22,40.74 110.64,40.74 110.64,31.09 111.76,29.97 X1.17
N$29  (via drill 0.41)
  Top 0.203: v97.74,52.73 96.62,51.61 89.61,51.61 87.27,53.95 K7.16
  Bottom 0.203: v97.74,52.73 97.74,69.19 95.81,69.19 95.61,68.99 95.61,67.97 93.78,67.97 IC1.12
N$30  (via drill 0.3)
  Top 0.305: v98.65,53.44 95.71,53.44 94.89,52.63 K8.S1 | v105.97,34.24 108.1,32.11 108.1,27.23 111.76,27.23 X1.16
  Bottom 0.305: v98.65,53.44 106.07,46.02 106.07,36.68 105.97,36.58 v105.97,34.24
N$31  (via drill 0.41)
  Top 0.203: v51.1,29.97 51.61,30.48 65.43,30.48 v69.19,26.72
  Bottom 0.203: v51.1,29.97 51,30.07 51,30.89 50.9,30.99 IC3.10 | v69.19,26.72 72.24,23.67 72.24,16.15 R33.2
N$33  (via drill 0.41)
  Top 0.203: v91.85,66.14 90.93,65.23 v89.71,65.23
  Bottom 0.203: v91.85,66.14 91.85,69.19 93.67,69.19 IC1.11 | v89.71,65.23 88.09,63.6 88.09,48.36 87.27,47.55 K8.16
N$34  (via drill 0.41)
  Top 0.203: v85.34,61.67 v79.76,61.67
  Bottom 0.203: v79.76,61.67 79.76,62.59 78.84,63.5 78.84,70.1 68.78,70.1 67.87,69.19 67.87,68.38 IC2.2 | v85.34,61.67 83.72,61.67 IC1.2
N$35  (via drill 0.41)
  Top 0.203: v68.58,64.21 71.83,60.96 75.59,60.96 78.03,58.52 79.45,58.52 v81.89,60.96
  Bottom 0.203: v68.58,64.21 68.58,68.17 68.48,68.28 IC2.3 | v81.89,60.96 82.3,61.37 82.3,61.98 83.11,62.79 83.62,62.79 IC1.3
N$36  (via drill 0.41)
  Top 0.203: v71.12,64.01 73.76,61.37 v77.11,61.37 | v78.54,62.79 78.84,63.09 v82.09,63.09
  Bottom 0.203: v71.12,64.01 69.19,65.94 69.19,68.28 IC2.4 | v78.54,62.79 v77.11,61.37 | v82.09,63.09 83.11,64.11 83.62,64.11 IC1.4
N$37  (via drill 0.41)
  Top 0.203: v72.03,64.21 72.75,63.5 81.28,63.5 v81.99,64.21
  Bottom 0.203: v72.03,64.21 69.6,66.65 69.6,67.26 69.7,67.36 69.7,68.28 IC2.5 | v81.99,64.21 83.11,65.33 83.62,65.33 IC1.5
N$38  (via drill 0.41)
  Top 0.203: v70.31,66.95 67.46,64.11 v63.6,64.11
  Bottom 0.203: v70.31,66.95 70.31,68.17 70.41,68.28 IC2.6 | v63.6,64.11 61.98,65.73 61.98,66.85 65.84,70.71 82.3,70.71 82.3,67.46 83.01,66.75 83.62,66.75 IC1.6
N$39  (via drill 0.41)
  Top 0.203: v71.02,66.34 71.83,65.53 v85.34,65.53
  Bottom 0.203: v71.02,66.34 71.02,68.28 IC2.7 | v85.34,65.53 85.04,65.84 85.04,67.16 84.33,67.87 83.72,67.87 IC1.7
N$40  (via drill 0.41)
  Top 0.203: v71.73,66.95 72.75,65.94 84.63,65.94 v85.75,67.06
  Bottom 0.203: v71.73,66.95 71.73,68.28 IC2.8 | v85.75,67.06 85.04,67.77 85.04,68.38 84.23,69.19 83.72,69.19 IC1.8
N$45  (via drill 0.41)
  Top 0.203: v73.56,8.84 2.13,8.84 2.13,25.5 7.62,30.99 8.84,30.99 9.35,31.5 JP5.6 | v71.93,48.16 71.42,48.67 62.08,48.67 JP3.6
  Bottom 0.203: v73.56,8.84 73.97,9.25 73.97,28.25 73.66,28.55 73.66,46.43 v71.93,48.16
N$47
  Bottom 0.203: R13.2 69.8,9.04 71.83,9.04 71.83,9.14 OK1.3
N$48
  Bottom 0.203: R14.2 69.9,4.17 71.83,4.17 OK1.1
N$49  (via drill 0.3)
  Top 0.152: v79.86,7.42 82.91,10.46 108.81,10.46 109.42,9.86 v112.57,9.86
  Bottom 0.152: v79.86,7.42 79.86,6.71 71.93,6.71 OK1.2 | v112.57,9.86 113.79,11.07 113.79,45.92 112.17,47.55 110.34,47.55 110.34,46.23 X1.10
N$50
  Bottom 0.203: R15.2 54.56,4.17 56.39,4.17 OK2.1
N$51  (via drill 0.41)
  Top 0.203: v72.95,64.41 73.46,64.92 85.04,64.92 87.07,62.89 96.42,62.89 104.85,54.46 v110.85,54.46
  Bottom 0.203: v72.95,64.41 72.95,63.8 71.83,62.69 71.83,61.27 71.73,61.16 IC2.21 | v110.85,54.46 114.2,51.1 114.2,9.86 108.1,3.76 81.48,3.76 81.48,4.06 OK1.8
N$52
  Bottom 0.203: R16.2 54.56,9.04 56.39,9.04 56.39,9.14 OK2.3
N$53
  Bottom 0.203: R17.2 39.12,4.17 40.95,4.17 OK3.1
N$54
  Bottom 0.203: R18.2 39.12,9.25 40.95,9.25 OK3.3
N$55  (via drill 0.3)
  Top 0.152: v48.97,6.81 49.28,7.11 v60.86,7.11 | v63.6,9.86 64.31,10.57 v68.17,10.57 | v71.63,32 72.54,32.92 76.1,32.92 76.81,32.21 86.77,32.21 86.87,32.11 v95.4,32.11 | v99.06,36.27 100.48,34.85 108.51,34.85 109.22,34.14 X1.6
  Bottom 0.152: v48.97,6.81 48.97,6.71 41.05,6.71 OK3.2 | v63.6,9.86 v60.86,7.11 | v68.17,10.57 71.63,14.02 71.63,15.24 71.42,15.44 71.42,20.93 71.63,21.13 71.63,23.37 68.48,26.52 68.48,28.25 71.63,31.39 v71.63,32 | v95.4,32.11 96.93,33.63 96.93,34.14 v99.06,36.27
N$56
  Bottom 0.203: R19.2 23.47,4.17 25.6,4.17 OK4.1
N$57
  Bottom 0.203: R20.2 23.57,9.25 25.6,9.25 OK4.3
N$58  (via drill 0.41)
  Top 0.203: v50.29,28.75 50.6,28.45 53.54,28.45 53.65,28.35 v59.13,28.35
  Bottom 0.203: v50.29,28.75 50.29,30.89 50.19,30.99 IC3.9 | v59.13,28.35 59.23,28.25 59.23,18.8 59.44,18.59 59.44,16.46 59.74,16.15 R34.2
N$59  (via drill 0.41)
  Top 0.203: v49.58,28.04 46.23,24.69 v46.23,23.77
  Bottom 0.203: v49.58,28.04 49.58,30.99 IC3.8 | v46.23,23.77 47.24,22.76 47.24,16.15 R35.2
N$60  (via drill 0.3)
  Top 0.152: v73.36,13.31 73.46,13.41 86.06,13.41 86.77,12.7 v105.66,12.7 | v109.73,16.76 113.89,20.93 113.89,42.27 109.22,42.27 X1.9
  Bottom 0.152: v73.36,13.31 73.36,13.21 71.93,11.79 OK1.4 | v109.73,16.76 v105.66,12.7
N$61  (via drill 0.3)
  Top 0.152: v109.73,17.68 110.64,18.59 111.05,18.59 113.49,21.03 113.49,39.52 109.22,39.52 X1.8
  Bottom 0.152: v109.73,17.68 105.87,13.82 105.87,13.41 102.41,13.41 97.43,8.43 97.43,5.49 80.57,5.49 80.06,4.98 80.06,2.95 64.11,2.95 60.45,6.6 56.49,6.6 OK2.2
N$62  (via drill 0.3)
  Top 0.152: v59.84,13.31 59.94,13.41 71.32,13.41 74.47,16.56 v88.9,16.56 | v91.75,22.15 94.49,24.89 103.43,24.89 106.17,27.64 v106.17,33.02 | v106.68,36.27 107.19,36.78 109.22,36.78 X1.7
  Bottom 0.152: v59.84,13.31 59.84,11.79 56.49,11.79 OK2.4 | v88.9,16.56 91.75,19.41 v91.75,22.15 | v106.17,33.02 106.68,33.53 v106.68,36.27
N$63  (via drill 0.41)
  Top 0.203: v59.94,19.51 59.94,19.1 59.44,18.59 59.44,16.76 54.15,16.76 v54.05,16.87 | v36.78,8.13 v52.83,8.13
  Bottom 0.203: v59.94,19.51 59.64,19.81 59.64,20.73 59.94,21.03 59.94,47.14 61.67,47.14 62.99,48.46 62.99,51.82 66.24,55.07 66.24,60.15 67.16,61.06 IC2.28 | v54.05,16.87 53.75,16.87 52.53,15.65 50.9,15.65 50.9,13.72 52.83,11.79 v52.83,8.13 | v36.78,8.13 35.15,8.13 35.15,9.14 OK4.6
N$64  (via drill 0.3)
  Top 0.152: v42.27,13.01 42.57,12.7 78.13,12.7 78.44,13.01 85.95,13.01 88.09,10.87 108.92,10.87 109.32,10.46 v111.96,10.46
  Bottom 0.152: v42.27,13.01 41.05,11.79 OK3.4 | v111.96,10.46 113.39,11.89 113.39,27.03 111.56,28.85 110.34,28.85 110.34,30.18 109.22,31.29 X1.5
N$65  (via drill 0.3)
  Top 0.152: v59.74,11.18 v30.18,11.18 | v63.3,15.14 v62.38,14.22 | v66.75,18.59 83.31,18.59 83.41,18.49 98.35,18.49 100.08,20.22 v105.16,20.22
  Bottom 0.152: v30.18,11.18 25.7,6.71 OK4.2 | v59.74,11.18 62.38,13.82 v62.38,14.22 | v66.75,18.59 v63.3,15.14 | v105.16,20.22 108.1,23.16 108.1,27.43 X1.4
N$66  (via drill 0.3)
  Top 0.152: v31.7,11.79 31.9,11.99 v36.68,11.99 | v37.39,14.02 39.32,15.95 60.86,15.95 61.06,15.75 v65.84,15.75 | v69.49,15.75 71.93,18.19 83.21,18.19 83.31,18.09 98.45,18.09 99.97,19.61 107.09,19.61 109.42,21.95 109.63,21.95 110.34,22.66 110.34,25.7 109.22,25.7 X1.3
  Bottom 0.152: v31.7,11.79 25.7,11.79 OK4.4 | v36.68,11.99 37.39,12.7 v37.39,14.02 | v69.49,15.75 v65.84,15.75
N$67
  Bottom 0.203: IC3.7 48.87,31.09 48.77,31.19 48.77,33.22 48.16,33.83 46.63,33.83 46.63,33.12 45.82,32.31 38.2,32.31 38.2,23.88 34.04,19.71 34.04,16.87 34.75,16.15 R36.2
N$68  (via drill 0.41)
  Top 0.203: v70.51,43.38 70.92,42.98 v84.12,42.98
  Bottom 0.203: v70.51,43.38 70.51,55.68 71.02,56.19 71.02,61.06 IC2.22 | v84.12,42.98 84.12,35.05 84.02,34.95 84.02,34.04 84.12,33.93 84.12,21.03 78.74,15.65 75.89,15.65 75.89,14.02 80.67,9.25 81.38,9.25 OK1.6
N$69  (via drill 0.41)
  Top 0.203: v62.79,43.38 v67.77,43.38 | v61.27,16.46 v63.5,16.46
  Bottom 0.203: v67.77,43.38 70.1,45.72 70.1,59.03 70.31,59.23 70.31,60.96 70.41,61.06 IC2.23 | v62.79,43.38 62.89,43.28 62.89,24.79 62.59,24.49 62.59,20.52 64.52,18.59 64.52,17.48 v63.5,16.46 | v61.27,16.46 60.66,15.85 60.66,15.44 58.12,12.9 55.07,12.9 55.07,10.87 55.47,10.46 64.21,10.46 64.21,5.89 65.94,4.17 OK2.8
N$70  (via drill 0.41)
  Top 0.203: v65.13,41.76 65.02,41.66 v62.18,41.66
  Bottom 0.203: v65.13,41.76 69.7,46.33 69.7,61.06 IC2.24 | v62.18,41.66 62.18,18.8 61.98,18.59 61.98,15.54 63.4,14.12 63.4,12.29 64.62,11.07 64.62,10.57 65.94,9.25 OK2.6
N$71  (via drill 0.41)
  Top 0.203: v68.99,52.12 70.61,50.49 v71.93,50.49 | v74.68,11.48 74.37,11.18 61.06,11.18 60.05,10.16 v54.05,10.16
  Bottom 0.203: v68.99,52.12 69.29,52.43 69.29,53.85 69.19,53.95 69.19,61.06 IC2.25 | v71.93,50.49 74.07,48.36 74.07,28.75 74.68,28.14 v74.68,11.48 | v54.05,10.16 53.54,9.65 53.54,7.11 50.6,4.17 OK3.8
N$72  (via drill 0.41)
  Top 0.203: v68.58,53.54 70.92,51.21 v71.22,51.21 | v75.39,26.72 v72.24,29.87 | v75.39,10.46 74.47,9.55 64.21,9.55 63.91,9.25 49.28,9.25 v48.97,9.55
  Bottom 0.203: v68.58,53.54 68.58,60.96 68.48,61.06 IC2.26 | v71.22,51.21 71.22,45.11 72.85,43.48 72.85,37.08 72.24,36.47 v72.24,29.87 | v75.39,10.46 v75.39,26.72 | v48.97,9.55 50.49,9.55 50.49,9.25 OK3.6
N$73  (via drill 0.41)
  Top 0.203: v67.77,59.74 67.06,60.45 60.86,60.45 60.45,60.05 59.03,60.05 57.81,61.27 v31.29,61.27 | v21.54,47.45 18.9,44.81 v12.29,44.81
  Bottom 0.203: v67.77,59.74 67.77,61.06 IC2.27 | v31.29,61.27 21.54,51.51 v21.54,47.45 | v12.29,44.81 10.46,42.98 2.13,42.98 2.13,10.57 9.75,2.95 35.05,2.95 35.05,4.06 OK4.8
N$74  (via drill 0.41)
  Top 0.203: v47.85,29.97 47.65,29.77 35.76,29.77 29.57,23.57 v25.09,23.57
  Bottom 0.203: v47.85,29.97 48.16,30.28 48.16,30.99 IC3.6 | v25.09,23.57 22.25,20.73 22.25,16.56 R37.2
N$75  (via drill 0.41)
  Top 0.203: v53.95,29.06 58.52,29.06 v59.23,29.77 | v57.2,36.88 56.9,36.58 v48.46,36.58
  Bottom 0.203: v53.95,29.06 53.95,25.81 53.44,25.3 IC3.15 | v59.23,29.77 59.54,30.07 59.54,34.54 v57.2,36.88 | v48.46,36.58 47.35,35.46 47.35,35.15 R29.2
N$76  (via drill 0.41)
  Top 0.203: v52.93,29.16 53.54,29.77 v56.39,29.77
  Bottom 0.203: v52.93,29.16 52.93,25.4 52.83,25.3 IC3.16 | v56.39,29.77 56.39,31.8 R28.2
N$77  (via drill 0.41)
  Top 0.203: v52.22,27.74 58.83,27.74 58.93,27.64 v64.62,27.64
  Bottom 0.203: v52.22,27.74 52.22,25.3 IC3.17 | v64.62,27.64 68.68,31.7 R27.2
N$78  (via drill 0.41)
  Top 0.203: v51.61,29.16 51.51,29.26 50.8,29.26 50.39,29.67 50.39,30.99 72.14,30.99 72.64,31.5 v80.16,31.5
  Bottom 0.203: v51.61,29.16 51.41,28.96 51.41,27.43 51.51,27.33 51.51,25.3 IC3.18 | v80.16,31.5 81.28,31.5 81.28,31.7 R26.2
N$79  (via drill 0.41)
  Top 0.203: v72.95,22.66 v52.93,22.66 | v73.25,17.48 73.56,17.17 v103.73,17.17
  Bottom 0.203: v52.93,22.66 51,24.59 51,25.09 50.9,25.2 IC3.19 | v72.95,22.66 73.25,22.35 v73.25,17.48 | v103.73,17.17 104.85,17.17 104.85,16.87 R25.2
N$80  (via drill 0.41)
  Top 0.203: v50.8,26.31 51.1,26.01 86.46,26.01 86.87,25.6 v99.87,25.6
  Bottom 0.203: v50.8,26.31 50.29,25.81 50.29,25.4 50.19,25.3 IC3.20 | v99.87,25.6 104.04,29.77 R24.2
N$81  (via drill 0.41)
  Top 0.203: v48.87,29.97 48.16,30.68 v37.49,30.68
  Bottom 0.203: v48.87,29.97 48.87,27.74 49.78,26.82 49.78,26.01 49.68,25.91 49.68,25.4 49.58,25.3 IC3.21 | v37.49,30.68 37.8,30.99 37.8,43.79 43.69,49.68 43.69,50.7 R23.2
N$82  (via drill 0.41)
  Top 0.203: v49.07,26.31 49.78,27.03 v56.79,27.03 | v50.6,43.38 52.53,45.31 v54.46,45.31
  Bottom 0.203: v49.07,26.31 49.07,25.4 48.97,25.3 IC3.22 | v56.79,27.03 58.52,28.75 58.52,30.79 59.13,31.39 59.13,33.93 53.65,39.42 50.6,39.42 v50.6,43.38 | v54.46,45.31 56.29,47.14 56.29,50.8 R22.2
RES
  Top 0.203: 15.75,11.48 13.21,11.48 RESETA.1 | 15.75,11.48 21.64,11.48 21.64,15.14 23.06,16.56 31.29,16.56 32.72,17.98 GND.RES | 15.75,11.48 RESET.1
SDI_MOSI  (via drill 0.41)
  Top 0.203: v74.78,36.88 75.49,36.17 88.7,36.17 89.1,35.76 95.1,35.76 98.86,32 100.08,32 101.3,30.79 JP2.2
  Bottom 0.203: v74.78,36.88 74.78,46.13 76,47.35 SERIAL.8
SDI_SCLK  (via drill 0.41)
  Top 0.203: v78.13,30.79 98.75,30.79 JP2.1
  Bottom 0.203: v78.13,30.79 75.69,33.22 75.69,44.5 76,44.81 SERIAL.7
SLIDER_IN  (via drill 0.41)
  Top 0.203: v63.3,24.18 62.59,23.47 50.6,23.47 50.6,18.09 GND.A0 | v63.91,51.71 66.45,54.25 73.56,54.25 POT1.2A
  Bottom 0.203: C7.1 75.79,55.68 73.66,55.68 73.66,54.36 POT1.2A 73.66,54.25 73.66,53.24 77.32,49.58 77.32,46.13 78.54,44.91 SERIAL.5 | v63.3,24.18 63.4,24.28 63.4,42.98 63.91,43.48 v63.91,51.71

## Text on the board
_tsilk: SCL SDA
_bsilk: SKAARHOJ 2013 | PCB-CMB-5-SHLD v09-13/4 | I2C PullUps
